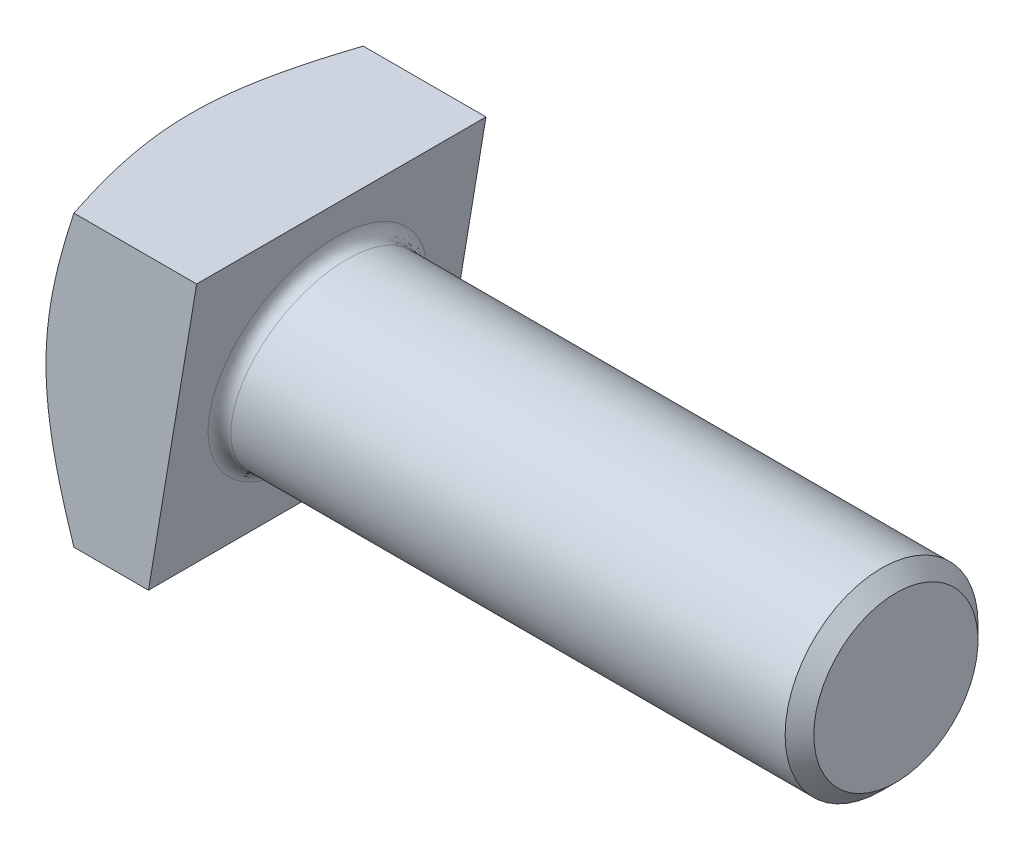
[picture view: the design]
ISO-10303-21;
HEADER;
FILE_DESCRIPTION(('STEP AP214'),'2;1');
FILE_NAME('part.step','',(''),(''),'','','');
FILE_SCHEMA(('AUTOMOTIVE_DESIGN { 1 0 10303 214 1 1 1 1 }'));
ENDSEC;
DATA;
#1=APPLICATION_CONTEXT('core data for automotive mechanical design processes');
#2=APPLICATION_PROTOCOL_DEFINITION('international standard','automotive_design',2000,#1);
#3=PRODUCT_CONTEXT('',#1,'mechanical');
#4=PRODUCT('Part','Part','',(#3));
#5=PRODUCT_RELATED_PRODUCT_CATEGORY('part','',(#4));
#6=PRODUCT_DEFINITION_FORMATION('','',#4);
#7=PRODUCT_DEFINITION_CONTEXT('part definition',#1,'design');
#8=PRODUCT_DEFINITION('design','',#6,#7);
#9=PRODUCT_DEFINITION_SHAPE('','',#8);
#10=(LENGTH_UNIT() NAMED_UNIT(*) SI_UNIT(.MILLI.,.METRE.));
#11=(NAMED_UNIT(*) PLANE_ANGLE_UNIT() SI_UNIT($,.RADIAN.));
#12=(NAMED_UNIT(*) SI_UNIT($,.STERADIAN.) SOLID_ANGLE_UNIT());
#13=UNCERTAINTY_MEASURE_WITH_UNIT(LENGTH_MEASURE(1.E-05),#10,'distance_accuracy_value','');
#14=(GEOMETRIC_REPRESENTATION_CONTEXT(3) GLOBAL_UNCERTAINTY_ASSIGNED_CONTEXT((#13)) GLOBAL_UNIT_ASSIGNED_CONTEXT((#10,
#11,#12)) REPRESENTATION_CONTEXT('',''));
#15=CARTESIAN_POINT('',(0.,0.,0.));
#16=DIRECTION('',(0.,0.,1.));
#17=DIRECTION('',(1.,0.,0.));
#18=AXIS2_PLACEMENT_3D('',#15,#16,#17);
#19=CARTESIAN_POINT('',(13.4958212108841,-19.05,19.05));
#20=DIRECTION('',(0.,-1.,0.));
#21=DIRECTION('',(0.,0.,-1.));
#22=AXIS2_PLACEMENT_3D('',#19,#20,#21);
#23=PLANE('',#22);
#24=DIRECTION('',(-1.,0.,0.));
#25=VECTOR('',#24,1.);
#26=CARTESIAN_POINT('',(13.4958212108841,-19.05,19.05));
#27=LINE('',#26,#25);
#28=CARTESIAN_POINT('',(13.4958212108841,-19.05,19.05));
#29=VERTEX_POINT('',#28);
#30=CARTESIAN_POINT('',(3.67952571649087,-19.05,19.05));
#31=VERTEX_POINT('',#30);
#32=EDGE_CURVE('E122',#29,#31,#27,.T.);
#33=ORIENTED_EDGE('',*,*,#32,.T.);
#34=CARTESIAN_POINT('',(11.2902215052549,-19.05,-38.8419170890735));
#35=CARTESIAN_POINT('',(11.0864153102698,-19.05,-38.3551118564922));
#36=CARTESIAN_POINT('',(10.8832370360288,-19.05,-37.868043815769));
#37=CARTESIAN_POINT('',(10.478273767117,-19.05,-36.893327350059));
#38=CARTESIAN_POINT('',(10.2764887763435,-19.05,-36.4056789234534));
#39=CARTESIAN_POINT('',(9.6734155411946,-19.05,-34.9417460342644));
#40=CARTESIAN_POINT('',(9.27442532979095,-19.05,-33.9645128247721));
#41=CARTESIAN_POINT('',(8.48368559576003,-19.05,-32.0062899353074));
#42=CARTESIAN_POINT('',(8.09194155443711,-19.05,-31.0252980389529));
#43=CARTESIAN_POINT('',(7.31784014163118,-19.05,-29.0596242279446));
#44=CARTESIAN_POINT('',(6.93548265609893,-19.05,-28.0749423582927));
#45=CARTESIAN_POINT('',(6.1781932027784,-19.05,-26.0895493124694));
#46=CARTESIAN_POINT('',(5.8033998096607,-19.05,-25.0887851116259));
#47=CARTESIAN_POINT('',(5.06928185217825,-19.05,-23.081553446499));
#48=CARTESIAN_POINT('',(4.70995768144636,-19.05,-22.075085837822));
#49=CARTESIAN_POINT('',(4.01126573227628,-19.05,-20.0549444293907));
#50=CARTESIAN_POINT('',(3.67190231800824,-19.05,-19.0412691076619));
#51=CARTESIAN_POINT('',(3.18260780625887,-19.05,-17.5144399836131));
#52=CARTESIAN_POINT('',(3.02280262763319,-19.05,-17.004448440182));
#53=CARTESIAN_POINT('',(2.71077373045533,-19.05,-15.9821547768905));
#54=CARTESIAN_POINT('',(2.55854993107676,-19.05,-15.4698526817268));
#55=CARTESIAN_POINT('',(2.18516308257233,-19.05,-14.1731993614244));
#56=CARTESIAN_POINT('',(1.96974702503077,-19.05,-13.3871770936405));
#57=CARTESIAN_POINT('',(1.56373956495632,-19.05,-11.8086936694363));
#58=CARTESIAN_POINT('',(1.37314818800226,-19.05,-11.0162325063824));
#59=CARTESIAN_POINT('',(1.02239164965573,-19.05,-9.42514563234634));
#60=CARTESIAN_POINT('',(0.862204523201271,-19.05,-8.62652480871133));
#61=CARTESIAN_POINT('',(0.578083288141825,-19.05,-7.02274351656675));
#62=CARTESIAN_POINT('',(0.454148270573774,-19.05,-6.21758321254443));
#63=CARTESIAN_POINT('',(0.300005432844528,-19.05,-5.00759649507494));
#64=CARTESIAN_POINT('',(0.253982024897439,-19.05,-4.60475053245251));
#65=CARTESIAN_POINT('',(0.172960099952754,-19.05,-3.79795792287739));
#66=CARTESIAN_POINT('',(0.137961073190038,-19.05,-3.39401132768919));
#67=CARTESIAN_POINT('',(0.0794934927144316,-19.05,-2.58528857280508));
#68=CARTESIAN_POINT('',(0.0560247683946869,-19.05,-2.18051242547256));
#69=CARTESIAN_POINT('',(0.0209711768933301,-19.05,-1.37044257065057));
#70=CARTESIAN_POINT('',(0.00938631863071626,-19.05,-0.965148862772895));
#71=CARTESIAN_POINT('',(-0.00171486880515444,-19.05,-0.154616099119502));
#72=CARTESIAN_POINT('',(-0.00123776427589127,-19.05,0.250622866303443));
#73=CARTESIAN_POINT('',(0.0117608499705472,-19.05,1.06090361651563));
#74=CARTESIAN_POINT('',(0.0242822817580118,-19.05,1.4659454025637));
#75=CARTESIAN_POINT('',(0.0611754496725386,-19.05,2.27549226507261));
#76=CARTESIAN_POINT('',(0.0855473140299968,-19.05,2.6799973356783));
#77=CARTESIAN_POINT('',(0.145770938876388,-19.05,3.48815676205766));
#78=CARTESIAN_POINT('',(0.181623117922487,-19.05,3.89181108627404));
#79=CARTESIAN_POINT('',(0.291723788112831,-19.05,4.96529995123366));
#80=CARTESIAN_POINT('',(0.375668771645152,-19.05,5.63415580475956));
#81=CARTESIAN_POINT('',(0.570959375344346,-19.05,6.96786634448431));
#82=CARTESIAN_POINT('',(0.682308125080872,-19.05,7.63272056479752));
#83=CARTESIAN_POINT('',(0.929086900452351,-19.05,8.95829697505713));
#84=CARTESIAN_POINT('',(1.06453043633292,-19.05,9.61901663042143));
#85=CARTESIAN_POINT('',(1.35607804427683,-19.05,10.9358292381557));
#86=CARTESIAN_POINT('',(1.51218163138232,-19.05,11.5919222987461));
#87=CARTESIAN_POINT('',(1.84291316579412,-19.05,12.9035714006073));
#88=CARTESIAN_POINT('',(2.01764633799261,-19.05,13.5591007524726));
#89=CARTESIAN_POINT('',(2.38205808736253,-19.05,14.8659747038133));
#90=CARTESIAN_POINT('',(2.57173673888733,-19.05,15.517319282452));
#91=CARTESIAN_POINT('',(2.96359176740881,-19.05,16.8160365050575));
#92=CARTESIAN_POINT('',(3.1657648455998,-19.05,17.46341014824));
#93=CARTESIAN_POINT('',(3.58064657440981,-19.05,18.7547595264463));
#94=CARTESIAN_POINT('',(3.793355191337,-19.05,19.3987352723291));
#95=CARTESIAN_POINT('',(4.23720030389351,-19.05,20.7119590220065));
#96=CARTESIAN_POINT('',(4.46873581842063,-19.05,21.3810718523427));
#97=CARTESIAN_POINT('',(4.93991757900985,-19.05,22.7164300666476));
#98=CARTESIAN_POINT('',(5.17956383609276,-19.05,23.3826754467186));
#99=CARTESIAN_POINT('',(5.66571185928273,-19.05,24.712706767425));
#100=CARTESIAN_POINT('',(5.91221408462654,-19.05,25.3764925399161));
#101=CARTESIAN_POINT('',(6.41101892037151,-19.05,26.7018819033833));
#102=CARTESIAN_POINT('',(6.66332156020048,-19.05,27.3634854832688));
#103=CARTESIAN_POINT('',(7.16922259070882,-19.05,28.6753217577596));
#104=CARTESIAN_POINT('',(7.42275067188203,-19.05,29.3255815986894));
#105=CARTESIAN_POINT('',(7.93393740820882,-19.05,30.6244763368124));
#106=CARTESIAN_POINT('',(8.19159607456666,-19.05,31.2731112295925));
#107=CARTESIAN_POINT('',(8.71041202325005,-19.05,32.5687880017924));
#108=CARTESIAN_POINT('',(8.97156840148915,-19.05,33.2158302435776));
#109=CARTESIAN_POINT('',(9.4969882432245,-19.05,34.5086430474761));
#110=CARTESIAN_POINT('',(9.76125166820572,-19.05,35.1544136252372));
#111=CARTESIAN_POINT('',(10.0268440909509,-19.05,35.7996345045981));
#112=B_SPLINE_CURVE_WITH_KNOTS('',3,(#34,#35,#36,#37,#38,#39,#40,#41,#42,#43,#44,#45,#46,#47,
#48,#49,#50,#51,#52,#53,#54,#55,#56,#57,#58,#59,#60,#61,#62,#63,#64,#65,#66,#67,#68,#69,#70,#71,
#72,#73,#74,#75,#76,#77,#78,#79,#80,#81,#82,#83,#84,#85,#86,#87,#88,#89,#90,#91,#92,#93,#94,#95,
#96,#97,#98,#99,#100,#101,#102,#103,#104,#105,#106,#107,#108,#109,#110,#111),.UNSPECIFIED.,.F.,
.F.,(4,2,2,2,2,2,2,2,2,2,2,2,2,2,2,2,2,2,2,2,2,2,2,2,2,2,2,2,2,2,2,2,2,2,2,2,2,2,4),(0.,
1.58323848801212,3.16648140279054,6.33309365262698,9.50201063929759,12.670889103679,
15.8767185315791,19.0826294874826,22.2892387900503,23.8925172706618,25.4957786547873,
27.9404596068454,30.3851430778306,32.8280536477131,35.2709029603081,36.4871758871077,
37.7033925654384,38.9195912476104,40.1357908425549,41.3513283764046,42.5668580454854,
43.7824008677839,44.997988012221,47.0196099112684,49.0414627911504,51.0644529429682,
53.0873956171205,55.1224393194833,57.1574931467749,59.1920119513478,61.2265242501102,
63.3505820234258,65.4746426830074,67.5988459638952,69.7230600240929,71.8168512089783,
73.9106480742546,76.0039137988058,78.0971536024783),.UNSPECIFIED.);
#113=CARTESIAN_POINT('',(0.,-19.05,0.));
#114=VERTEX_POINT('',#113);
#115=EDGE_CURVE('E100',#31,#114,#112,.F.);
#116=ORIENTED_EDGE('',*,*,#115,.T.);
#117=CARTESIAN_POINT('',(3.67952571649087,-19.05,-19.05));
#118=VERTEX_POINT('',#117);
#119=EDGE_CURVE('E112',#114,#118,#112,.F.);
#120=ORIENTED_EDGE('',*,*,#119,.T.);
#121=DIRECTION('',(-1.,0.,0.));
#122=VECTOR('',#121,1.);
#123=CARTESIAN_POINT('',(13.4958212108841,-19.05,-19.05));
#124=LINE('',#123,#122);
#125=CARTESIAN_POINT('',(13.4958212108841,-19.05,-19.05));
#126=VERTEX_POINT('',#125);
#127=EDGE_CURVE('E287',#126,#118,#124,.T.);
#128=ORIENTED_EDGE('',*,*,#127,.F.);
#129=DIRECTION('',(0.,0.,-1.));
#130=VECTOR('',#129,1.);
#131=CARTESIAN_POINT('',(13.4958212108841,-19.05,19.05));
#132=LINE('',#131,#130);
#133=EDGE_CURVE('E307',#29,#126,#132,.T.);
#134=ORIENTED_EDGE('',*,*,#133,.F.);
#135=EDGE_LOOP('',(#33,#116,#120,#128,#134));
#136=FACE_BOUND('',#135,.T.);
#137=ADVANCED_FACE('F39',(#136),#23,.T.);
#138=CARTESIAN_POINT('',(0.,19.05,19.05));
#139=DIRECTION('',(0.,1.,0.));
#140=DIRECTION('',(-1.,0.,0.));
#141=AXIS2_PLACEMENT_3D('',#138,#139,#140);
#142=PLANE('',#141);
#143=DIRECTION('',(1.,0.,0.));
#144=VECTOR('',#143,1.);
#145=CARTESIAN_POINT('',(0.,19.05,-19.05));
#146=LINE('',#145,#144);
#147=CARTESIAN_POINT('',(3.67952571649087,19.05,-19.05));
#148=VERTEX_POINT('',#147);
#149=CARTESIAN_POINT('',(19.8374,19.05,-19.05));
#150=VERTEX_POINT('',#149);
#151=EDGE_CURVE('E303',#148,#150,#146,.T.);
#152=ORIENTED_EDGE('',*,*,#151,.F.);
#153=CARTESIAN_POINT('',(11.290221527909,19.05,-38.8419171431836));
#154=CARTESIAN_POINT('',(11.08641533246,19.05,-38.3551119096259));
#155=CARTESIAN_POINT('',(10.8832370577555,19.05,-37.868043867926));
#156=CARTESIAN_POINT('',(10.4782737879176,19.05,-36.8933274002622));
#157=CARTESIAN_POINT('',(10.2764887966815,19.05,-36.4056789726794));
#158=CARTESIAN_POINT('',(9.67341556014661,19.05,-34.9417460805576));
#159=CARTESIAN_POINT('',(9.27442534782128,19.05,-33.9645128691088));
#160=CARTESIAN_POINT('',(8.48368561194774,19.05,-32.0062899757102));
#161=CARTESIAN_POINT('',(8.09194156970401,19.05,-31.0252980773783));
#162=CARTESIAN_POINT('',(7.31784015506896,19.05,-29.0596242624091));
#163=CARTESIAN_POINT('',(6.93548266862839,19.05,-28.0749423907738));
#164=CARTESIAN_POINT('',(6.17819321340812,19.05,-26.0895493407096));
#165=CARTESIAN_POINT('',(5.80339981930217,19.05,-25.0887851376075));
#166=CARTESIAN_POINT('',(5.06928185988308,19.05,-23.081553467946));
#167=CARTESIAN_POINT('',(4.70995768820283,19.05,-22.0750858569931));
#168=CARTESIAN_POINT('',(4.01126573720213,19.05,-20.0549444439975));
#169=CARTESIAN_POINT('',(3.67190232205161,19.05,-19.0412691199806));
#170=CARTESIAN_POINT('',(3.18260780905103,19.05,-17.5144399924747));
#171=CARTESIAN_POINT('',(3.02280263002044,19.05,-17.0044484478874));
#172=CARTESIAN_POINT('',(2.71077373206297,19.05,-15.9821547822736));
#173=CARTESIAN_POINT('',(2.55854993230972,19.05,-15.4698526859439));
#174=CARTESIAN_POINT('',(2.18516308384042,19.05,-14.1731993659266));
#175=CARTESIAN_POINT('',(1.96974702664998,19.05,-13.3871770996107));
#176=CARTESIAN_POINT('',(1.56373956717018,19.05,-11.8086936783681));
#177=CARTESIAN_POINT('',(1.37314819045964,19.05,-11.0162325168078));
#178=CARTESIAN_POINT('',(1.02239165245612,19.05,-9.42514564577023));
#179=CARTESIAN_POINT('',(0.862204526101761,19.05,-8.62652482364));
#180=CARTESIAN_POINT('',(0.578083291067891,19.05,-7.02274353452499));
#181=CARTESIAN_POINT('',(0.454148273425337,19.05,-6.21758323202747));
#182=CARTESIAN_POINT('',(0.300005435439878,19.05,-5.00759651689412));
#183=CARTESIAN_POINT('',(0.253982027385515,19.05,-4.60475055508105));
#184=CARTESIAN_POINT('',(0.172960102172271,19.05,-3.79795794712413));
#185=CARTESIAN_POINT('',(0.137961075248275,19.05,-3.39401135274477));
#186=CARTESIAN_POINT('',(0.0794934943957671,19.05,-2.58528859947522));
#187=CARTESIAN_POINT('',(0.056024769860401,19.05,-2.1805124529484));
#188=CARTESIAN_POINT('',(0.0209711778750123,19.05,-1.37044259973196));
#189=CARTESIAN_POINT('',(0.009386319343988,19.05,-0.965148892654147));
#190=CARTESIAN_POINT('',(-0.00171486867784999,19.05,-0.15461613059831));
#191=CARTESIAN_POINT('',(-0.00123776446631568,19.05,0.250622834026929));
#192=CARTESIAN_POINT('',(0.0117608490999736,19.05,1.0609035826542));
#193=CARTESIAN_POINT('',(0.024282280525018,19.05,1.46594536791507));
#194=CARTESIAN_POINT('',(0.0611754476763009,19.05,2.27549222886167));
#195=CARTESIAN_POINT('',(0.08554731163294,19.05,2.67999729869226));
#196=CARTESIAN_POINT('',(0.145770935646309,19.05,3.48815672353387));
#197=CARTESIAN_POINT('',(0.1816231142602,19.05,3.89181104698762));
#198=CARTESIAN_POINT('',(0.291723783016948,19.05,4.96529990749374));
#199=CARTESIAN_POINT('',(0.375668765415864,19.05,5.63415575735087));
#200=CARTESIAN_POINT('',(0.570959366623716,19.05,6.96786628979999));
#201=CARTESIAN_POINT('',(0.682308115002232,19.05,7.63272050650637));
#202=CARTESIAN_POINT('',(0.929086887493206,19.05,8.95829690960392));
#203=CARTESIAN_POINT('',(1.064530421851,19.05,9.61901656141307));
#204=CARTESIAN_POINT('',(1.35607802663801,19.05,10.9358291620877));
#205=CARTESIAN_POINT('',(1.5121816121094,19.05,11.5919222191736));
#206=CARTESIAN_POINT('',(1.84291314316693,19.05,12.9035713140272));
#207=CARTESIAN_POINT('',(2.01764631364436,19.05,13.5591006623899));
#208=CARTESIAN_POINT('',(2.38205805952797,19.05,14.8659746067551));
#209=CARTESIAN_POINT('',(2.5717367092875,19.05,15.5173191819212));
#210=CARTESIAN_POINT('',(2.96359173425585,19.05,16.8160363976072));
#211=CARTESIAN_POINT('',(3.16576481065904,19.05,17.4634100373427));
#212=CARTESIAN_POINT('',(3.58064653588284,19.05,18.7547594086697));
#213=CARTESIAN_POINT('',(3.79335515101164,19.05,19.3987351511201));
#214=CARTESIAN_POINT('',(4.23720025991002,19.05,20.7119588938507));
#215=CARTESIAN_POINT('',(4.46873577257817,19.05,21.3810717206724));
#216=CARTESIAN_POINT('',(4.93991752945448,19.05,22.716429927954));
#217=CARTESIAN_POINT('',(5.17956378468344,19.05,23.3826753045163));
#218=CARTESIAN_POINT('',(5.66571180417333,19.05,24.7127066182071));
#219=CARTESIAN_POINT('',(5.91221402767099,19.05,25.3764923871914));
#220=CARTESIAN_POINT('',(6.41101885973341,19.05,26.701881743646));
#221=CARTESIAN_POINT('',(6.66332149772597,19.05,27.3634853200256));
#222=CARTESIAN_POINT('',(7.16922252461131,19.05,28.6753215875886));
#223=CARTESIAN_POINT('',(7.42275060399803,19.05,29.3255814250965));
#224=CARTESIAN_POINT('',(7.93393733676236,19.05,30.6244761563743));
#225=CARTESIAN_POINT('',(8.19159600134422,19.05,31.2731110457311));
#226=CARTESIAN_POINT('',(8.71041194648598,19.05,32.5687878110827));
#227=CARTESIAN_POINT('',(8.97156832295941,19.05,33.2158300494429));
#228=CARTESIAN_POINT('',(9.496988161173,19.05,34.5086428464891));
#229=CARTESIAN_POINT('',(9.76125158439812,19.05,35.154413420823));
#230=CARTESIAN_POINT('',(10.0268440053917,19.05,35.7996342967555));
#231=B_SPLINE_CURVE_WITH_KNOTS('',3,(#153,#154,#155,#156,#157,#158,#159,#160,#161,#162,#163,
#164,#165,#166,#167,#168,#169,#170,#171,#172,#173,#174,#175,#176,#177,#178,#179,#180,#181,#182,
#183,#184,#185,#186,#187,#188,#189,#190,#191,#192,#193,#194,#195,#196,#197,#198,#199,#200,#201,
#202,#203,#204,#205,#206,#207,#208,#209,#210,#211,#212,#213,#214,#215,#216,#217,#218,#219,#220,
#221,#222,#223,#224,#225,#226,#227,#228,#229,#230),.UNSPECIFIED.,.F.,.F.,(4,2,2,2,2,2,2,2,2,2,2,
2,2,2,2,2,2,2,2,2,2,2,2,2,2,2,2,2,2,2,2,2,2,2,2,2,2,2,4),(0.,1.58323849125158,3.16648140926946,
6.33309366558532,9.50201065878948,12.6708891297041,15.8767185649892,19.0826295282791,
22.2892388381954,23.89251732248,25.4957787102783,27.9404596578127,30.385143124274,
32.8280536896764,35.2709029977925,36.4871759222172,37.7033925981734,38.919591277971,
40.1357908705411,41.3513284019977,42.5668580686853,43.7824008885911,44.9979880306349,
47.0196099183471,49.0414627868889,51.0644529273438,53.0873955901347,55.1224392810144,
57.1574930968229,59.1920118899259,61.2265241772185,63.3505819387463,65.4746425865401,
67.5988458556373,69.7230599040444,71.8168510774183,73.9106479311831,76.0039136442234,
78.0971534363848),.UNSPECIFIED.);
#232=CARTESIAN_POINT('',(0.,19.05,0.));
#233=VERTEX_POINT('',#232);
#234=EDGE_CURVE('E106',#148,#233,#231,.T.);
#235=ORIENTED_EDGE('',*,*,#234,.T.);
#236=CARTESIAN_POINT('',(3.67952571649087,19.05,19.05));
#237=VERTEX_POINT('',#236);
#238=EDGE_CURVE('E132',#233,#237,#231,.T.);
#239=ORIENTED_EDGE('',*,*,#238,.T.);
#240=DIRECTION('',(1.,0.,0.));
#241=VECTOR('',#240,1.);
#242=CARTESIAN_POINT('',(0.,19.05,19.05));
#243=LINE('',#242,#241);
#244=CARTESIAN_POINT('',(19.8374,19.05,19.05));
#245=VERTEX_POINT('',#244);
#246=EDGE_CURVE('E291',#237,#245,#243,.T.);
#247=ORIENTED_EDGE('',*,*,#246,.T.);
#248=DIRECTION('',(0.,0.,-1.));
#249=VECTOR('',#248,1.);
#250=CARTESIAN_POINT('',(19.8374,19.05,19.05));
#251=LINE('',#250,#249);
#252=EDGE_CURVE('E297',#245,#150,#251,.T.);
#253=ORIENTED_EDGE('',*,*,#252,.T.);
#254=EDGE_LOOP('',(#152,#235,#239,#247,#253));
#255=FACE_BOUND('',#254,.T.);
#256=ADVANCED_FACE('F138',(#255),#142,.T.);
#257=CARTESIAN_POINT('',(0.,-19.05,19.05));
#258=DIRECTION('',(0.,0.,-1.));
#259=DIRECTION('',(-1.,0.,0.));
#260=AXIS2_PLACEMENT_3D('',#257,#258,#259);
#261=PLANE('',#260);
#262=CARTESIAN_POINT('',(11.2902215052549,-38.8419170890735,19.05));
#263=CARTESIAN_POINT('',(11.0864153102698,-38.3551118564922,19.05));
#264=CARTESIAN_POINT('',(10.8832370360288,-37.868043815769,19.05));
#265=CARTESIAN_POINT('',(10.478273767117,-36.893327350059,19.05));
#266=CARTESIAN_POINT('',(10.2764887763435,-36.4056789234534,19.05));
#267=CARTESIAN_POINT('',(9.67341554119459,-34.9417460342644,19.05));
#268=CARTESIAN_POINT('',(9.27442532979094,-33.9645128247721,19.05));
#269=CARTESIAN_POINT('',(8.48368559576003,-32.0062899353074,19.05));
#270=CARTESIAN_POINT('',(8.09194155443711,-31.0252980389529,19.05));
#271=CARTESIAN_POINT('',(7.31784014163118,-29.0596242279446,19.05));
#272=CARTESIAN_POINT('',(6.93548265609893,-28.0749423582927,19.05));
#273=CARTESIAN_POINT('',(6.1781932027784,-26.0895493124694,19.05));
#274=CARTESIAN_POINT('',(5.8033998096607,-25.0887851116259,19.05));
#275=CARTESIAN_POINT('',(5.06928185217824,-23.081553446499,19.05));
#276=CARTESIAN_POINT('',(4.70995768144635,-22.075085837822,19.05));
#277=CARTESIAN_POINT('',(4.01126573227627,-20.0549444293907,19.05));
#278=CARTESIAN_POINT('',(3.67190231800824,-19.0412691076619,19.05));
#279=CARTESIAN_POINT('',(3.18260780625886,-17.5144399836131,19.05));
#280=CARTESIAN_POINT('',(3.02280262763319,-17.004448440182,19.05));
#281=CARTESIAN_POINT('',(2.71077373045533,-15.9821547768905,19.05));
#282=CARTESIAN_POINT('',(2.55854993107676,-15.4698526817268,19.05));
#283=CARTESIAN_POINT('',(2.18516308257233,-14.1731993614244,19.05));
#284=CARTESIAN_POINT('',(1.96974702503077,-13.3871770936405,19.05));
#285=CARTESIAN_POINT('',(1.56373956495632,-11.8086936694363,19.05));
#286=CARTESIAN_POINT('',(1.37314818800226,-11.0162325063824,19.05));
#287=CARTESIAN_POINT('',(1.02239164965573,-9.42514563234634,19.05));
#288=CARTESIAN_POINT('',(0.862204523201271,-8.62652480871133,19.05));
#289=CARTESIAN_POINT('',(0.578083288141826,-7.02274351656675,19.05));
#290=CARTESIAN_POINT('',(0.454148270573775,-6.21758321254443,19.05));
#291=CARTESIAN_POINT('',(0.300005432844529,-5.00759649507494,19.05));
#292=CARTESIAN_POINT('',(0.25398202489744,-4.60475053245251,19.05));
#293=CARTESIAN_POINT('',(0.172960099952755,-3.79795792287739,19.05));
#294=CARTESIAN_POINT('',(0.137961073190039,-3.39401132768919,19.05));
#295=CARTESIAN_POINT('',(0.0794934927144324,-2.58528857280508,19.05));
#296=CARTESIAN_POINT('',(0.0560247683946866,-2.18051242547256,19.05));
#297=CARTESIAN_POINT('',(0.0209711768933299,-1.37044257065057,19.05));
#298=CARTESIAN_POINT('',(0.00938631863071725,-0.965148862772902,19.05));
#299=CARTESIAN_POINT('',(-0.00171486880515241,-0.15461609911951,19.05));
#300=CARTESIAN_POINT('',(-0.0012377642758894,0.250622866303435,19.05));
#301=CARTESIAN_POINT('',(0.0117608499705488,1.06090361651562,19.05));
#302=CARTESIAN_POINT('',(0.0242822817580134,1.46594540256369,19.05));
#303=CARTESIAN_POINT('',(0.0611754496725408,2.2754922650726,19.05));
#304=CARTESIAN_POINT('',(0.0855473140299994,2.6799973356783,19.05));
#305=CARTESIAN_POINT('',(0.14577093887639,3.48815676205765,19.05));
#306=CARTESIAN_POINT('',(0.181623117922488,3.89181108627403,19.05));
#307=CARTESIAN_POINT('',(0.291723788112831,4.96529995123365,19.05));
#308=CARTESIAN_POINT('',(0.375668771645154,5.63415580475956,19.05));
#309=CARTESIAN_POINT('',(0.570959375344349,6.9678663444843,19.05));
#310=CARTESIAN_POINT('',(0.682308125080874,7.63272056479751,19.05));
#311=CARTESIAN_POINT('',(0.929086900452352,8.95829697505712,19.05));
#312=CARTESIAN_POINT('',(1.06453043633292,9.61901663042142,19.05));
#313=CARTESIAN_POINT('',(1.35607804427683,10.9358292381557,19.05));
#314=CARTESIAN_POINT('',(1.51218163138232,11.5919222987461,19.05));
#315=CARTESIAN_POINT('',(1.84291316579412,12.9035714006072,19.05));
#316=CARTESIAN_POINT('',(2.01764633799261,13.5591007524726,19.05));
#317=CARTESIAN_POINT('',(2.38205808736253,14.8659747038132,19.05));
#318=CARTESIAN_POINT('',(2.57173673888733,15.5173192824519,19.05));
#319=CARTESIAN_POINT('',(2.96359176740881,16.8160365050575,19.05));
#320=CARTESIAN_POINT('',(3.1657648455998,17.46341014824,19.05));
#321=CARTESIAN_POINT('',(3.58064657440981,18.7547595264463,19.05));
#322=CARTESIAN_POINT('',(3.793355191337,19.398735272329,19.05));
#323=CARTESIAN_POINT('',(4.23720030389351,20.7119590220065,19.05));
#324=CARTESIAN_POINT('',(4.46873581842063,21.3810718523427,19.05));
#325=CARTESIAN_POINT('',(4.93991757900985,22.7164300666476,19.05));
#326=CARTESIAN_POINT('',(5.17956383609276,23.3826754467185,19.05));
#327=CARTESIAN_POINT('',(5.66571185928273,24.712706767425,19.05));
#328=CARTESIAN_POINT('',(5.91221408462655,25.3764925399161,19.05));
#329=CARTESIAN_POINT('',(6.41101892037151,26.7018819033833,19.05));
#330=CARTESIAN_POINT('',(6.66332156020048,27.3634854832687,19.05));
#331=CARTESIAN_POINT('',(7.16922259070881,28.6753217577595,19.05));
#332=CARTESIAN_POINT('',(7.42275067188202,29.3255815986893,19.05));
#333=CARTESIAN_POINT('',(7.93393740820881,30.6244763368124,19.05));
#334=CARTESIAN_POINT('',(8.19159607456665,31.2731112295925,19.05));
#335=CARTESIAN_POINT('',(8.71041202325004,32.5687880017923,19.05));
#336=CARTESIAN_POINT('',(8.97156840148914,33.2158302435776,19.05));
#337=CARTESIAN_POINT('',(9.49698824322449,34.508643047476,19.05));
#338=CARTESIAN_POINT('',(9.76125166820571,35.1544136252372,19.05));
#339=CARTESIAN_POINT('',(10.0268440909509,35.7996345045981,19.05));
#340=B_SPLINE_CURVE_WITH_KNOTS('',3,(#262,#263,#264,#265,#266,#267,#268,#269,#270,#271,#272,
#273,#274,#275,#276,#277,#278,#279,#280,#281,#282,#283,#284,#285,#286,#287,#288,#289,#290,#291,
#292,#293,#294,#295,#296,#297,#298,#299,#300,#301,#302,#303,#304,#305,#306,#307,#308,#309,#310,
#311,#312,#313,#314,#315,#316,#317,#318,#319,#320,#321,#322,#323,#324,#325,#326,#327,#328,#329,
#330,#331,#332,#333,#334,#335,#336,#337,#338,#339),.UNSPECIFIED.,.F.,.F.,(4,2,2,2,2,2,2,2,2,2,2,
2,2,2,2,2,2,2,2,2,2,2,2,2,2,2,2,2,2,2,2,2,2,2,2,2,2,2,4),(0.,1.58323848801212,3.16648140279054,
6.33309365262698,9.50201063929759,12.670889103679,15.8767185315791,19.0826294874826,
22.2892387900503,23.8925172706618,25.4957786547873,27.9404596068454,30.3851430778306,
32.8280536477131,35.2709029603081,36.4871758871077,37.7033925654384,38.9195912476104,
40.1357908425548,41.3513283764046,42.5668580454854,43.7824008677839,44.997988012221,
47.0196099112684,49.0414627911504,51.0644529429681,53.0873956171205,55.1224393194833,
57.1574931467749,59.1920119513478,61.2265242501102,63.3505820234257,65.4746426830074,
67.5988459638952,69.7230600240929,71.8168512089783,73.9106480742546,76.0039137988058,
78.0971536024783),.UNSPECIFIED.);
#341=CARTESIAN_POINT('',(0.,0.,19.05));
#342=VERTEX_POINT('',#341);
#343=EDGE_CURVE('E101',#31,#342,#340,.T.);
#344=ORIENTED_EDGE('',*,*,#343,.F.);
#345=ORIENTED_EDGE('',*,*,#32,.F.);
#346=DIRECTION('',(-0.164186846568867,-0.986429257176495,0.));
#347=VECTOR('',#346,1.);
#348=CARTESIAN_POINT('',(19.8374,19.05,19.05));
#349=LINE('',#348,#347);
#350=EDGE_CURVE('E295',#245,#29,#349,.T.);
#351=ORIENTED_EDGE('',*,*,#350,.F.);
#352=ORIENTED_EDGE('',*,*,#246,.F.);
#353=EDGE_CURVE('E65',#342,#237,#340,.T.);
#354=ORIENTED_EDGE('',*,*,#353,.F.);
#355=EDGE_LOOP('',(#344,#345,#351,#352,#354));
#356=FACE_BOUND('',#355,.T.);
#357=ADVANCED_FACE('F168',(#356),#261,.F.);
#358=CARTESIAN_POINT('',(0.,-19.05,-19.05));
#359=DIRECTION('',(0.,0.,-1.));
#360=DIRECTION('',(-1.,0.,0.));
#361=AXIS2_PLACEMENT_3D('',#358,#359,#360);
#362=PLANE('',#361);
#363=ORIENTED_EDGE('',*,*,#127,.T.);
#364=CARTESIAN_POINT('',(11.2902215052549,-38.8419170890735,-19.05));
#365=CARTESIAN_POINT('',(11.0864153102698,-38.3551118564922,-19.05));
#366=CARTESIAN_POINT('',(10.8832370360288,-37.868043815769,-19.05));
#367=CARTESIAN_POINT('',(10.478273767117,-36.893327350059,-19.05));
#368=CARTESIAN_POINT('',(10.2764887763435,-36.4056789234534,-19.05));
#369=CARTESIAN_POINT('',(9.67341554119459,-34.9417460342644,-19.05));
#370=CARTESIAN_POINT('',(9.27442532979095,-33.9645128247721,-19.05));
#371=CARTESIAN_POINT('',(8.48368559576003,-32.0062899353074,-19.05));
#372=CARTESIAN_POINT('',(8.09194155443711,-31.0252980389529,-19.05));
#373=CARTESIAN_POINT('',(7.31784014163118,-29.0596242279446,-19.05));
#374=CARTESIAN_POINT('',(6.93548265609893,-28.0749423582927,-19.05));
#375=CARTESIAN_POINT('',(6.17819320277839,-26.0895493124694,-19.05));
#376=CARTESIAN_POINT('',(5.80339980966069,-25.0887851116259,-19.05));
#377=CARTESIAN_POINT('',(5.06928185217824,-23.0815534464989,-19.05));
#378=CARTESIAN_POINT('',(4.70995768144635,-22.075085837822,-19.05));
#379=CARTESIAN_POINT('',(4.01126573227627,-20.0549444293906,-19.05));
#380=CARTESIAN_POINT('',(3.67190231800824,-19.0412691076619,-19.05));
#381=CARTESIAN_POINT('',(3.18260780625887,-17.5144399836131,-19.05));
#382=CARTESIAN_POINT('',(3.02280262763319,-17.004448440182,-19.05));
#383=CARTESIAN_POINT('',(2.71077373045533,-15.9821547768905,-19.05));
#384=CARTESIAN_POINT('',(2.55854993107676,-15.4698526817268,-19.05));
#385=CARTESIAN_POINT('',(2.18516308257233,-14.1731993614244,-19.05));
#386=CARTESIAN_POINT('',(1.96974702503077,-13.3871770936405,-19.05));
#387=CARTESIAN_POINT('',(1.56373956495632,-11.8086936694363,-19.05));
#388=CARTESIAN_POINT('',(1.37314818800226,-11.0162325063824,-19.05));
#389=CARTESIAN_POINT('',(1.02239164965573,-9.42514563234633,-19.05));
#390=CARTESIAN_POINT('',(0.862204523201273,-8.62652480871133,-19.05));
#391=CARTESIAN_POINT('',(0.578083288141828,-7.02274351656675,-19.05));
#392=CARTESIAN_POINT('',(0.454148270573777,-6.21758321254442,-19.05));
#393=CARTESIAN_POINT('',(0.300005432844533,-5.00759649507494,-19.05));
#394=CARTESIAN_POINT('',(0.253982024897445,-4.60475053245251,-19.05));
#395=CARTESIAN_POINT('',(0.17296009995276,-3.79795792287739,-19.05));
#396=CARTESIAN_POINT('',(0.137961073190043,-3.39401132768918,-19.05));
#397=CARTESIAN_POINT('',(0.0794934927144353,-2.58528857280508,-19.05));
#398=CARTESIAN_POINT('',(0.0560247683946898,-2.18051242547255,-19.05));
#399=CARTESIAN_POINT('',(0.0209711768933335,-1.37044257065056,-19.05));
#400=CARTESIAN_POINT('',(0.0093863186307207,-0.965148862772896,-19.05));
#401=CARTESIAN_POINT('',(-0.00171486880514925,-0.154616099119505,-19.05));
#402=CARTESIAN_POINT('',(-0.00123776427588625,0.250622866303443,-19.05));
#403=CARTESIAN_POINT('',(0.0117608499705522,1.06090361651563,-19.05));
#404=CARTESIAN_POINT('',(0.024282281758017,1.4659454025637,-19.05));
#405=CARTESIAN_POINT('',(0.061175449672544,2.27549226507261,-19.05));
#406=CARTESIAN_POINT('',(0.0855473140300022,2.6799973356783,-19.05));
#407=CARTESIAN_POINT('',(0.145770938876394,3.48815676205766,-19.05));
#408=CARTESIAN_POINT('',(0.181623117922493,3.89181108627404,-19.05));
#409=CARTESIAN_POINT('',(0.291723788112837,4.96529995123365,-19.05));
#410=CARTESIAN_POINT('',(0.375668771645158,5.63415580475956,-19.05));
#411=CARTESIAN_POINT('',(0.570959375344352,6.96786634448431,-19.05));
#412=CARTESIAN_POINT('',(0.68230812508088,7.63272056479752,-19.05));
#413=CARTESIAN_POINT('',(0.929086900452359,8.95829697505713,-19.05));
#414=CARTESIAN_POINT('',(1.06453043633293,9.61901663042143,-19.05));
#415=CARTESIAN_POINT('',(1.35607804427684,10.9358292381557,-19.05));
#416=CARTESIAN_POINT('',(1.51218163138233,11.5919222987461,-19.05));
#417=CARTESIAN_POINT('',(1.84291316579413,12.9035714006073,-19.05));
#418=CARTESIAN_POINT('',(2.01764633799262,13.5591007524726,-19.05));
#419=CARTESIAN_POINT('',(2.38205808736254,14.8659747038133,-19.05));
#420=CARTESIAN_POINT('',(2.57173673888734,15.517319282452,-19.05));
#421=CARTESIAN_POINT('',(2.96359176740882,16.8160365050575,-19.05));
#422=CARTESIAN_POINT('',(3.16576484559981,17.46341014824,-19.05));
#423=CARTESIAN_POINT('',(3.58064657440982,18.7547595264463,-19.05));
#424=CARTESIAN_POINT('',(3.79335519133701,19.3987352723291,-19.05));
#425=CARTESIAN_POINT('',(4.23720030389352,20.7119590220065,-19.05));
#426=CARTESIAN_POINT('',(4.46873581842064,21.3810718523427,-19.05));
#427=CARTESIAN_POINT('',(4.93991757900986,22.7164300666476,-19.05));
#428=CARTESIAN_POINT('',(5.17956383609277,23.3826754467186,-19.05));
#429=CARTESIAN_POINT('',(5.66571185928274,24.712706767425,-19.05));
#430=CARTESIAN_POINT('',(5.91221408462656,25.3764925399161,-19.05));
#431=CARTESIAN_POINT('',(6.41101892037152,26.7018819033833,-19.05));
#432=CARTESIAN_POINT('',(6.66332156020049,27.3634854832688,-19.05));
#433=CARTESIAN_POINT('',(7.16922259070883,28.6753217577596,-19.05));
#434=CARTESIAN_POINT('',(7.42275067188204,29.3255815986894,-19.05));
#435=CARTESIAN_POINT('',(7.93393740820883,30.6244763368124,-19.05));
#436=CARTESIAN_POINT('',(8.19159607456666,31.2731112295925,-19.05));
#437=CARTESIAN_POINT('',(8.71041202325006,32.5687880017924,-19.05));
#438=CARTESIAN_POINT('',(8.97156840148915,33.2158302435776,-19.05));
#439=CARTESIAN_POINT('',(9.49698824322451,34.508643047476,-19.05));
#440=CARTESIAN_POINT('',(9.76125166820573,35.1544136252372,-19.05));
#441=CARTESIAN_POINT('',(10.0268440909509,35.7996345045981,-19.05));
#442=B_SPLINE_CURVE_WITH_KNOTS('',3,(#364,#365,#366,#367,#368,#369,#370,#371,#372,#373,#374,
#375,#376,#377,#378,#379,#380,#381,#382,#383,#384,#385,#386,#387,#388,#389,#390,#391,#392,#393,
#394,#395,#396,#397,#398,#399,#400,#401,#402,#403,#404,#405,#406,#407,#408,#409,#410,#411,#412,
#413,#414,#415,#416,#417,#418,#419,#420,#421,#422,#423,#424,#425,#426,#427,#428,#429,#430,#431,
#432,#433,#434,#435,#436,#437,#438,#439,#440,#441),.UNSPECIFIED.,.F.,.F.,(4,2,2,2,2,2,2,2,2,2,2,
2,2,2,2,2,2,2,2,2,2,2,2,2,2,2,2,2,2,2,2,2,2,2,2,2,2,2,4),(0.,1.58323848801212,3.16648140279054,
6.33309365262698,9.50201063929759,12.670889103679,15.8767185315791,19.0826294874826,
22.2892387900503,23.8925172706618,25.4957786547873,27.9404596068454,30.3851430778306,
32.8280536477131,35.2709029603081,36.4871758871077,37.7033925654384,38.9195912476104,
40.1357908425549,41.3513283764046,42.5668580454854,43.7824008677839,44.997988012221,
47.0196099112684,49.0414627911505,51.0644529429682,53.0873956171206,55.1224393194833,
57.1574931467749,59.1920119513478,61.2265242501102,63.3505820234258,65.4746426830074,
67.5988459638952,69.723060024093,71.8168512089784,73.9106480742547,76.0039137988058,
78.0971536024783),.UNSPECIFIED.);
#443=CARTESIAN_POINT('',(0.,0.,-19.05));
#444=VERTEX_POINT('',#443);
#445=EDGE_CURVE('E115',#118,#444,#442,.T.);
#446=ORIENTED_EDGE('',*,*,#445,.T.);
#447=EDGE_CURVE('E151',#444,#148,#442,.T.);
#448=ORIENTED_EDGE('',*,*,#447,.T.);
#449=ORIENTED_EDGE('',*,*,#151,.T.);
#450=DIRECTION('',(-0.164186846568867,-0.986429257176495,0.));
#451=VECTOR('',#450,1.);
#452=CARTESIAN_POINT('',(19.8374,19.05,-19.05));
#453=LINE('',#452,#451);
#454=EDGE_CURVE('E299',#150,#126,#453,.T.);
#455=ORIENTED_EDGE('',*,*,#454,.T.);
#456=EDGE_LOOP('',(#363,#446,#448,#449,#455));
#457=FACE_BOUND('',#456,.T.);
#458=ADVANCED_FACE('F171',(#457),#362,.T.);
#459=CARTESIAN_POINT('',(19.8374,19.05,19.05));
#460=DIRECTION('',(0.986429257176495,-0.164186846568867,0.));
#461=DIRECTION('',(0.164186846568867,0.986429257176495,0.));
#462=AXIS2_PLACEMENT_3D('',#459,#460,#461);
#463=PLANE('',#462);
#464=CARTESIAN_POINT('',(16.7082587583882,0.250220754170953,0.));
#465=DIRECTION('',(0.986429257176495,-0.164186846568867,0.));
#466=DIRECTION('',(-0.164186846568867,-0.986429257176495,0.));
#467=AXIS2_PLACEMENT_3D('',#464,#465,#466);
#468=ELLIPSE('',#467,14.4196858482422,14.224);
#469=CARTESIAN_POINT('',(14.3407360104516,-13.973779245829,0.));
#470=VERTEX_POINT('',#469);
#471=EDGE_CURVE('E11',#470,#470,#468,.F.);
#472=ORIENTED_EDGE('',*,*,#471,.T.);
#473=EDGE_LOOP('',(#472));
#474=FACE_BOUND('',#473,.T.);
#475=ORIENTED_EDGE('',*,*,#454,.F.);
#476=ORIENTED_EDGE('',*,*,#252,.F.);
#477=ORIENTED_EDGE('',*,*,#350,.T.);
#478=ORIENTED_EDGE('',*,*,#133,.T.);
#479=EDGE_LOOP('',(#475,#476,#477,#478));
#480=FACE_BOUND('',#479,.T.);
#481=ADVANCED_FACE('F176',(#474,#480),#463,.T.);
#482=CARTESIAN_POINT('',(0.,0.,0.));
#483=DIRECTION('',(-1.,0.,0.));
#484=DIRECTION('',(0.,0.,1.));
#485=AXIS2_PLACEMENT_3D('',#482,#483,#484);
#486=CYLINDRICAL_SURFACE('',#485,12.7);
#487=CARTESIAN_POINT('',(18.2115769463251,0.,0.));
#488=DIRECTION('',(-0.983064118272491,0.183261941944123,0.));
#489=DIRECTION('',(-0.183261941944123,-0.98306411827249,0.));
#490=AXIS2_PLACEMENT_3D('',#487,#488,#489);
#491=ELLIPSE('',#490,12.9187911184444,12.7);
#492=CARTESIAN_POINT('',(15.8440541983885,-12.7,0.));
#493=VERTEX_POINT('',#492);
#494=EDGE_CURVE('E50',#493,#493,#491,.F.);
#495=ORIENTED_EDGE('',*,*,#494,.T.);
#496=EDGE_LOOP('',(#495));
#497=FACE_BOUND('',#496,.T.);
#498=CARTESIAN_POINT('',(90.9768506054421,0.,0.));
#499=DIRECTION('',(-1.,0.,0.));
#500=DIRECTION('',(0.,0.,1.));
#501=AXIS2_PLACEMENT_3D('',#498,#499,#500);
#502=CIRCLE('',#501,12.7);
#503=CARTESIAN_POINT('',(90.9768506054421,0.,12.7));
#504=VERTEX_POINT('',#503);
#505=EDGE_CURVE('E285',#504,#504,#502,.T.);
#506=ORIENTED_EDGE('',*,*,#505,.T.);
#507=EDGE_LOOP('',(#506));
#508=FACE_BOUND('',#507,.T.);
#509=ADVANCED_FACE('F172',(#497,#508),#486,.T.);
#510=CARTESIAN_POINT('',(90.9768506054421,0.,0.));
#511=DIRECTION('',(-1.,0.,0.));
#512=DIRECTION('',(0.,0.,1.));
#513=AXIS2_PLACEMENT_3D('',#510,#511,#512);
#514=CONICAL_SURFACE('',#513,12.7,0.785398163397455);
#515=CARTESIAN_POINT('',(92.8666106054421,0.,0.));
#516=DIRECTION('',(-1.,0.,0.));
#517=DIRECTION('',(0.,0.,1.));
#518=AXIS2_PLACEMENT_3D('',#515,#516,#517);
#519=CIRCLE('',#518,10.81024);
#520=CARTESIAN_POINT('',(92.8666106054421,0.,10.81024));
#521=VERTEX_POINT('',#520);
#522=EDGE_CURVE('E166',#521,#521,#519,.T.);
#523=ORIENTED_EDGE('',*,*,#522,.T.);
#524=EDGE_LOOP('',(#523));
#525=FACE_BOUND('',#524,.T.);
#526=ORIENTED_EDGE('',*,*,#505,.F.);
#527=EDGE_LOOP('',(#526));
#528=FACE_BOUND('',#527,.T.);
#529=ADVANCED_FACE('F185',(#525,#528),#514,.T.);
#530=CARTESIAN_POINT('',(92.8666106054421,10.81024,0.));
#531=DIRECTION('',(1.,0.,0.));
#532=DIRECTION('',(0.,0.,-1.));
#533=AXIS2_PLACEMENT_3D('',#530,#531,#532);
#534=PLANE('',#533);
#535=ORIENTED_EDGE('',*,*,#522,.F.);
#536=EDGE_LOOP('',(#535));
#537=FACE_BOUND('',#536,.T.);
#538=ADVANCED_FACE('F145',(#537),#534,.T.);
#539=CARTESIAN_POINT('',(0.,0.,0.));
#540=DIRECTION('',(1.,0.,0.));
#541=DIRECTION('',(0.,1.,0.));
#542=AXIS2_PLACEMENT_3D('',#539,#540,#541);
#543=CONICAL_SURFACE('',#542,19.05,1.13446401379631);
#544=ORIENTED_EDGE('',*,*,#447,.F.);
#545=CARTESIAN_POINT('',(0.,0.,0.));
#546=DIRECTION('',(-1.,0.,0.));
#547=DIRECTION('',(0.,-1.,0.));
#548=AXIS2_PLACEMENT_3D('',#545,#546,#547);
#549=CIRCLE('',#548,19.05);
#550=EDGE_CURVE('E57',#233,#444,#549,.T.);
#551=ORIENTED_EDGE('',*,*,#550,.F.);
#552=ORIENTED_EDGE('',*,*,#234,.F.);
#553=EDGE_LOOP('',(#544,#551,#552));
#554=FACE_BOUND('',#553,.T.);
#555=ADVANCED_FACE('F141',(#554),#543,.T.);
#556=EDGE_CURVE('E109',#444,#114,#549,.T.);
#557=ORIENTED_EDGE('',*,*,#556,.F.);
#558=ORIENTED_EDGE('',*,*,#445,.F.);
#559=ORIENTED_EDGE('',*,*,#119,.F.);
#560=EDGE_LOOP('',(#557,#558,#559));
#561=FACE_BOUND('',#560,.T.);
#562=ADVANCED_FACE('F113',(#561),#543,.T.);
#563=ORIENTED_EDGE('',*,*,#353,.T.);
#564=ORIENTED_EDGE('',*,*,#238,.F.);
#565=EDGE_CURVE('E107',#342,#233,#549,.T.);
#566=ORIENTED_EDGE('',*,*,#565,.F.);
#567=EDGE_LOOP('',(#563,#564,#566));
#568=FACE_BOUND('',#567,.T.);
#569=ADVANCED_FACE('F146',(#568),#543,.T.);
#570=ORIENTED_EDGE('',*,*,#343,.T.);
#571=EDGE_CURVE('E96',#114,#342,#549,.T.);
#572=ORIENTED_EDGE('',*,*,#571,.F.);
#573=ORIENTED_EDGE('',*,*,#115,.F.);
#574=EDGE_LOOP('',(#570,#572,#573));
#575=FACE_BOUND('',#574,.T.);
#576=ADVANCED_FACE('F98',(#575),#543,.T.);
#577=CARTESIAN_POINT('',(0.,-19.05,19.05));
#578=DIRECTION('',(-1.,0.,0.));
#579=DIRECTION('',(0.,0.,1.));
#580=AXIS2_PLACEMENT_3D('',#577,#578,#579);
#581=PLANE('',#580);
#582=ORIENTED_EDGE('',*,*,#571,.T.);
#583=ORIENTED_EDGE('',*,*,#565,.T.);
#584=ORIENTED_EDGE('',*,*,#550,.T.);
#585=ORIENTED_EDGE('',*,*,#556,.T.);
#586=EDGE_LOOP('',(#582,#583,#584,#585));
#587=FACE_BOUND('',#586,.T.);
#588=ADVANCED_FACE('F123',(#587),#581,.T.);
#589=CARTESIAN_POINT('',(15.8440541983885,-12.7,0.));
#590=CARTESIAN_POINT('',(14.5527510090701,-12.7,0.));
#591=CARTESIAN_POINT('',(14.3407360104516,-13.973779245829,0.));
#592=CARTESIAN_POINT('',(15.8440541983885,-12.7,-0.55418458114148));
#593=CARTESIAN_POINT('',(14.5527510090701,-12.7,-0.563562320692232));
#594=CARTESIAN_POINT('',(14.3407360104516,-13.973779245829,-0.620686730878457));
#595=CARTESIAN_POINT('',(15.8508271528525,-12.6636681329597,-1.10836916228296));
#596=CARTESIAN_POINT('',(14.5590086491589,-12.6624043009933,-1.12735199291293));
#597=CARTESIAN_POINT('',(14.3475089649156,-13.9330875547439,-1.24137346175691));
#598=CARTESIAN_POINT('',(15.8777965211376,-12.5189975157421,-2.20725308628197));
#599=CARTESIAN_POINT('',(14.5838983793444,-12.512867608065,-2.24441934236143));
#600=CARTESIAN_POINT('',(14.3744783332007,-13.7710564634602,-2.4721234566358));
#601=CARTESIAN_POINT('',(15.8979992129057,-12.4106250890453,-2.75194787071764));
#602=CARTESIAN_POINT('',(14.6025562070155,-12.4007719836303,-2.7981313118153));
#603=CARTESIAN_POINT('',(14.3946810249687,-13.6496793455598,-3.08218161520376));
#604=CARTESIAN_POINT('',(15.9514760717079,-12.1237614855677,-3.8225388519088));
#605=CARTESIAN_POINT('',(14.6518795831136,-12.1044387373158,-3.8852175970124));
#606=CARTESIAN_POINT('',(14.4481578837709,-13.3283921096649,-4.28124351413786));
#607=CARTESIAN_POINT('',(15.984762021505,-11.9452071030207,-4.3484176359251));
#608=CARTESIAN_POINT('',(14.6825945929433,-11.9199039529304,-4.41896686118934));
#609=CARTESIAN_POINT('',(14.4814438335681,-13.1284112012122,-4.87022775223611));
#610=CARTESIAN_POINT('',(16.0638305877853,-11.5210630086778,-5.37239341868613));
#611=CARTESIAN_POINT('',(14.7554482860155,-11.4822013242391,-5.45671717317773));
#612=CARTESIAN_POINT('',(14.5605123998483,-12.6533698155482,-6.01708062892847));
#613=CARTESIAN_POINT('',(16.1096290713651,-11.275388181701,-5.87045416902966));
#614=CARTESIAN_POINT('',(14.7976563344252,-11.2286167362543,-5.96100031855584));
#615=CARTESIAN_POINT('',(14.6063108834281,-12.3782140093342,-6.57490866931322));
#616=CARTESIAN_POINT('',(16.2129354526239,-10.7212262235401,-6.83029208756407));
#617=CARTESIAN_POINT('',(14.8927073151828,-10.6575535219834,-6.93099597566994));
#618=CARTESIAN_POINT('',(14.7096172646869,-11.757552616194,-7.64992713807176));
#619=CARTESIAN_POINT('',(16.2704614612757,-10.4126419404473,-7.2920115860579));
#620=CARTESIAN_POINT('',(14.9456342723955,-10.3395700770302,-7.39687251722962));
#621=CARTESIAN_POINT('',(14.7671432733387,-11.4119382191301,-8.16705297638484));
#622=CARTESIAN_POINT('',(16.3962369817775,-9.7379497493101,-8.1712886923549));
#623=CARTESIAN_POINT('',(15.061145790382,-9.64558061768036,-8.28198069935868));
#624=CARTESIAN_POINT('',(14.8929187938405,-10.6562829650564,-9.15184333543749));
#625=CARTESIAN_POINT('',(16.4645048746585,-9.37174324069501,-8.58876851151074));
#626=CARTESIAN_POINT('',(15.1238228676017,-9.26901876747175,-8.70124326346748));
#627=CARTESIAN_POINT('',(14.9611866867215,-10.2461316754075,-9.61942073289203));
#628=CARTESIAN_POINT('',(16.6105965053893,-8.58807021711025,-9.37244251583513));
#629=CARTESIAN_POINT('',(15.2576884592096,-8.46475862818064,-9.48594199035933));
#630=CARTESIAN_POINT('',(15.1072783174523,-9.36841788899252,-10.4971356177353));
#631=CARTESIAN_POINT('',(16.6884370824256,-8.1705133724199,-9.73854382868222));
#632=CARTESIAN_POINT('',(15.3289714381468,-8.03649279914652,-9.85127189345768));
#633=CARTESIAN_POINT('',(15.1851188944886,-8.90075422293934,-10.9071690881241));
#634=CARTESIAN_POINT('',(16.8523444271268,-7.29127228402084,-10.413210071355));
#635=CARTESIAN_POINT('',(15.4787564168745,-7.13658949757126,-10.5219435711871));
#636=CARTESIAN_POINT('',(15.3490262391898,-7.91600420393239,-11.6627952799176));
#637=CARTESIAN_POINT('',(16.9384250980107,-6.82951345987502,-10.7216750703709));
#638=CARTESIAN_POINT('',(15.5573484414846,-6.66441115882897,-10.8270485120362));
#639=CARTESIAN_POINT('',(15.4351069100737,-7.39883432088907,-12.0082760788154));
#640=CARTESIAN_POINT('',(17.1173432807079,-5.86975038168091,-11.2757952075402));
#641=CARTESIAN_POINT('',(15.720338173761,-5.68517412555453,-11.372235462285));
#642=CARTESIAN_POINT('',(15.6140250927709,-6.32389967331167,-12.6288906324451));
#643=CARTESIAN_POINT('',(17.2101909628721,-5.37169157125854,-11.5213531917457));
#644=CARTESIAN_POINT('',(15.8048156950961,-5.17763591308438,-11.6119662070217));
#645=CARTESIAN_POINT('',(15.7068727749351,-5.76607380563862,-12.9039155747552));
#646=CARTESIAN_POINT('',(17.401058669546,-4.34782817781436,-11.9454517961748));
#647=CARTESIAN_POINT('',(15.97806979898,-4.13673086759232,-12.0225818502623));
#648=CARTESIAN_POINT('',(15.897740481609,-4.61934680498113,-13.3789060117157));
#649=CARTESIAN_POINT('',(17.4990850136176,-3.82198969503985,-12.1239082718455));
#650=CARTESIAN_POINT('',(16.0669111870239,-3.60297468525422,-12.1930249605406));
#651=CARTESIAN_POINT('',(15.9957668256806,-4.03040770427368,-13.578777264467));
#652=CARTESIAN_POINT('',(17.6986368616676,-2.75154233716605,-12.4107341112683));
#653=CARTESIAN_POINT('',(16.2473226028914,-2.5190687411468,-12.4625147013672));
#654=CARTESIAN_POINT('',(16.1953186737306,-2.83150666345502,-13.9000222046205));
#655=CARTESIAN_POINT('',(17.8001653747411,-2.20691732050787,-12.5190415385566));
#656=CARTESIAN_POINT('',(16.338938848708,-1.96864130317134,-12.5610585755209));
#657=CARTESIAN_POINT('',(16.2968471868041,-2.22152664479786,-14.0213265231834));
#658=CARTESIAN_POINT('',(18.0049877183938,-1.10819767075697,-12.6636908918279));
#659=CARTESIAN_POINT('',(16.5232965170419,-0.861026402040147,-12.6855050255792));
#660=CARTESIAN_POINT('',(16.5016695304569,-0.990960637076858,-14.1833337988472));
#661=CARTESIAN_POINT('',(18.1082823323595,-0.554098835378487,-12.7));
#662=CARTESIAN_POINT('',(16.6160633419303,-0.30368632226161,-12.7108768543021));
#663=CARTESIAN_POINT('',(16.6049641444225,-0.370369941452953,-14.224));
#664=CARTESIAN_POINT('',(18.3148715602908,0.554098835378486,-12.7));
#665=CARTESIAN_POINT('',(16.8011169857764,0.80810997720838,-12.6890449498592));
#666=CARTESIAN_POINT('',(16.8115533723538,0.870811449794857,-14.224));
#667=CARTESIAN_POINT('',(18.4181661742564,1.10819767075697,-12.6636908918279));
#668=CARTESIAN_POINT('',(16.8934075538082,1.36258872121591,-12.6413167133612));
#669=CARTESIAN_POINT('',(16.9148479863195,1.49140214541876,-14.1833337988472));
#670=CARTESIAN_POINT('',(18.6229885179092,2.20691732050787,-12.5190415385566));
#671=CARTESIAN_POINT('',(17.0759328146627,2.45919457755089,-12.4746356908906));
#672=CARTESIAN_POINT('',(17.1196703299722,2.72196815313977,-14.0213265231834));
#673=CARTESIAN_POINT('',(18.7245170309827,2.75154233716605,-12.4107341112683));
#674=CARTESIAN_POINT('',(17.1661501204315,3.00121722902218,-12.3551981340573));
#675=CARTESIAN_POINT('',(17.2211988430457,3.33194817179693,-13.9000222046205));
#676=CARTESIAN_POINT('',(18.9240688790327,3.82198969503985,-12.1239082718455));
#677=CARTESIAN_POINT('',(17.3430120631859,4.06379805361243,-12.0476793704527));
#678=CARTESIAN_POINT('',(17.4207506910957,4.53084921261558,-13.578777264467));
#679=CARTESIAN_POINT('',(19.0220952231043,4.34782817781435,-11.9454517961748));
#680=CARTESIAN_POINT('',(17.4296199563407,4.584135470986,-11.8591840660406));
#681=CARTESIAN_POINT('',(17.5187770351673,5.11978831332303,-13.3789060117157));
#682=CARTESIAN_POINT('',(19.2129629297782,5.37169157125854,-11.5213531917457));
#683=CARTESIAN_POINT('',(17.5978327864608,5.59475270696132,-11.417276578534));
#684=CARTESIAN_POINT('',(17.7096447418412,6.26651531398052,-12.9039155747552));
#685=CARTESIAN_POINT('',(19.3058106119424,5.86975038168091,-11.2757952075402));
#686=CARTESIAN_POINT('',(17.679384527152,6.08471292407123,-11.1635477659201));
#687=CARTESIAN_POINT('',(17.8024924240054,6.82434118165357,-12.6288906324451));
#688=CARTESIAN_POINT('',(19.4847287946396,6.82951345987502,-10.7216750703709));
#689=CARTESIAN_POINT('',(17.8361653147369,7.026646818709,-10.5959366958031));
#690=CARTESIAN_POINT('',(17.9814106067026,7.89927582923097,-12.0082760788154));
#691=CARTESIAN_POINT('',(19.5708094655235,7.29127228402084,-10.413210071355));
#692=CARTESIAN_POINT('',(17.911328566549,7.47822520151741,-10.2818565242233));
#693=CARTESIAN_POINT('',(18.0674912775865,8.4164457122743,-11.6627952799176));
#694=CARTESIAN_POINT('',(19.7347168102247,8.1705133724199,-9.73854382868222));
#695=CARTESIAN_POINT('',(18.0541429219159,8.33624922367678,-9.59921399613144));
#696=CARTESIAN_POINT('',(18.2313986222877,9.40119573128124,-10.9071690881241));
#697=CARTESIAN_POINT('',(19.812557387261,8.58807021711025,-9.37244251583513));
#698=CARTESIAN_POINT('',(18.121720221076,8.74225144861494,-9.23058694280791));
#699=CARTESIAN_POINT('',(18.309239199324,9.86885939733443,-10.4971356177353));
#700=CARTESIAN_POINT('',(19.9586490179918,9.37174324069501,-8.58876851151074));
#701=CARTESIAN_POINT('',(18.248318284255,9.50284851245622,-8.44528882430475));
#702=CARTESIAN_POINT('',(18.4553308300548,10.7465731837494,-9.61942073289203));
#703=CARTESIAN_POINT('',(20.0269169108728,9.7379497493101,-8.17128869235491));
#704=CARTESIAN_POINT('',(18.3072623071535,9.85698229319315,-8.02869308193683));
#705=CARTESIAN_POINT('',(18.5235987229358,11.1567244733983,-9.1518433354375));
#706=CARTESIAN_POINT('',(20.1526924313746,10.4126419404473,-7.2920115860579));
#707=CARTESIAN_POINT('',(18.4157041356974,10.5084972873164,-7.15451860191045));
#708=CARTESIAN_POINT('',(18.6493742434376,11.912379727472,-8.16705297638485));
#709=CARTESIAN_POINT('',(20.2102184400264,10.7212262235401,-6.83029208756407));
#710=CARTESIAN_POINT('',(18.4651275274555,10.8054314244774,-6.69715367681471));
#711=CARTESIAN_POINT('',(18.7069002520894,12.2579941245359,-7.64992713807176));
#712=CARTESIAN_POINT('',(20.3135248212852,11.275388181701,-5.87045416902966));
#713=CARTESIAN_POINT('',(18.5537979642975,11.33816053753,-5.74898662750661));
#714=CARTESIAN_POINT('',(18.8102066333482,12.8786555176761,-6.57490866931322));
#715=CARTESIAN_POINT('',(20.359323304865,11.5210630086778,-5.37239341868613));
#716=CARTESIAN_POINT('',(18.5929780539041,11.5735532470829,-5.25852673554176));
#717=CARTESIAN_POINT('',(18.856005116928,13.1538113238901,-6.01708062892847));
#718=CARTESIAN_POINT('',(20.4383918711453,11.9452071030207,-4.3484176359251));
#719=CARTESIAN_POINT('',(18.6605923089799,11.9797775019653,-4.25207613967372));
#720=CARTESIAN_POINT('',(18.9350736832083,13.6288527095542,-4.87022775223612));
#721=CARTESIAN_POINT('',(20.4716778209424,12.1237614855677,-3.8225388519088));
#722=CARTESIAN_POINT('',(18.688971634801,12.1502795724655,-3.7365377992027));
#723=CARTESIAN_POINT('',(18.9683596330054,13.8288336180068,-4.28124351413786));
#724=CARTESIAN_POINT('',(20.5251546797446,12.4106250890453,-2.75194787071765));
#725=CARTESIAN_POINT('',(18.7345739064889,12.4242565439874,-2.68809190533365));
#726=CARTESIAN_POINT('',(19.0218364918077,14.1501208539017,-3.08218161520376));
#727=CARTESIAN_POINT('',(20.5453573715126,12.5189975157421,-2.20725308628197));
#728=CARTESIAN_POINT('',(18.751757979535,12.5274978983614,-2.15572126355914));
#729=CARTESIAN_POINT('',(19.0420391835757,14.2714979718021,-2.47212345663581));
#730=CARTESIAN_POINT('',(20.5723267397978,12.6636681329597,-1.10836916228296));
#731=CARTESIAN_POINT('',(18.7747162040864,12.6654301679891,-1.08194171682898));
#732=CARTESIAN_POINT('',(19.0690085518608,14.4335290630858,-1.24137346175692));
#733=CARTESIAN_POINT('',(20.5790996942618,12.7,-0.554184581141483));
#734=CARTESIAN_POINT('',(18.780470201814,12.7,-0.541122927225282));
#735=CARTESIAN_POINT('',(19.0757815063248,14.474220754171,-0.620686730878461));
#736=CARTESIAN_POINT('',(20.5790996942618,12.7,0.55418458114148));
#737=CARTESIAN_POINT('',(18.780470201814,12.7,0.541122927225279));
#738=CARTESIAN_POINT('',(19.0757815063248,14.474220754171,0.620686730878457));
#739=CARTESIAN_POINT('',(20.5723267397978,12.6636681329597,1.10836916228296));
#740=CARTESIAN_POINT('',(18.7747162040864,12.6654301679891,1.08194171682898));
#741=CARTESIAN_POINT('',(19.0690085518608,14.4335290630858,1.24137346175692));
#742=CARTESIAN_POINT('',(20.5453573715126,12.5189975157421,2.20725308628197));
#743=CARTESIAN_POINT('',(18.751757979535,12.5274978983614,2.15572126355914));
#744=CARTESIAN_POINT('',(19.0420391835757,14.2714979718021,2.4721234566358));
#745=CARTESIAN_POINT('',(20.5251546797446,12.4106250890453,2.75194787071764));
#746=CARTESIAN_POINT('',(18.7345739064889,12.4242565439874,2.68809190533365));
#747=CARTESIAN_POINT('',(19.0218364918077,14.1501208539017,3.08218161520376));
#748=CARTESIAN_POINT('',(20.4716778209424,12.1237614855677,3.8225388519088));
#749=CARTESIAN_POINT('',(18.688971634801,12.1502795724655,3.7365377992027));
#750=CARTESIAN_POINT('',(18.9683596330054,13.8288336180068,4.28124351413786));
#751=CARTESIAN_POINT('',(20.4383918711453,11.9452071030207,4.3484176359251));
#752=CARTESIAN_POINT('',(18.6605923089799,11.9797775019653,4.25207613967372));
#753=CARTESIAN_POINT('',(18.9350736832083,13.6288527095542,4.87022775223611));
#754=CARTESIAN_POINT('',(20.359323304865,11.5210630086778,5.37239341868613));
#755=CARTESIAN_POINT('',(18.5929780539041,11.5735532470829,5.25852673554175));
#756=CARTESIAN_POINT('',(18.856005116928,13.1538113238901,6.01708062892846));
#757=CARTESIAN_POINT('',(20.3135248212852,11.275388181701,5.87045416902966));
#758=CARTESIAN_POINT('',(18.5537979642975,11.33816053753,5.7489866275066));
#759=CARTESIAN_POINT('',(18.8102066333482,12.8786555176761,6.57490866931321));
#760=CARTESIAN_POINT('',(20.2102184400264,10.7212262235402,6.83029208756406));
#761=CARTESIAN_POINT('',(18.4651275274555,10.8054314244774,6.69715367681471));
#762=CARTESIAN_POINT('',(18.7069002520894,12.2579941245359,7.64992713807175));
#763=CARTESIAN_POINT('',(20.1526924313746,10.4126419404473,7.29201158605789));
#764=CARTESIAN_POINT('',(18.4157041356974,10.5084972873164,7.15451860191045));
#765=CARTESIAN_POINT('',(18.6493742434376,11.912379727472,8.16705297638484));
#766=CARTESIAN_POINT('',(20.0269169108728,9.7379497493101,8.1712886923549));
#767=CARTESIAN_POINT('',(18.3072623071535,9.85698229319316,8.02869308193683));
#768=CARTESIAN_POINT('',(18.5235987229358,11.1567244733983,9.15184333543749));
#769=CARTESIAN_POINT('',(19.9586490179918,9.37174324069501,8.58876851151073));
#770=CARTESIAN_POINT('',(18.248318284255,9.50284851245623,8.44528882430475));
#771=CARTESIAN_POINT('',(18.4553308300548,10.7465731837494,9.61942073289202));
#772=CARTESIAN_POINT('',(19.812557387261,8.58807021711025,9.37244251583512));
#773=CARTESIAN_POINT('',(18.121720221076,8.74225144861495,9.23058694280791));
#774=CARTESIAN_POINT('',(18.309239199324,9.86885939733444,10.4971356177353));
#775=CARTESIAN_POINT('',(19.7347168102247,8.1705133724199,9.73854382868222));
#776=CARTESIAN_POINT('',(18.0541429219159,8.33624922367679,9.59921399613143));
#777=CARTESIAN_POINT('',(18.2313986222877,9.40119573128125,10.9071690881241));
#778=CARTESIAN_POINT('',(19.5708094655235,7.29127228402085,10.413210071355));
#779=CARTESIAN_POINT('',(17.911328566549,7.47822520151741,10.2818565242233));
#780=CARTESIAN_POINT('',(18.0674912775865,8.4164457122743,11.6627952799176));
#781=CARTESIAN_POINT('',(19.4847287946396,6.82951345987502,10.7216750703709));
#782=CARTESIAN_POINT('',(17.8361653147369,7.026646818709,10.5959366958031));
#783=CARTESIAN_POINT('',(17.9814106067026,7.89927582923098,12.0082760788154));
#784=CARTESIAN_POINT('',(19.3058106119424,5.86975038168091,11.2757952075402));
#785=CARTESIAN_POINT('',(17.679384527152,6.08471292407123,11.1635477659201));
#786=CARTESIAN_POINT('',(17.8024924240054,6.82434118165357,12.6288906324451));
#787=CARTESIAN_POINT('',(19.2129629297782,5.37169157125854,11.5213531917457));
#788=CARTESIAN_POINT('',(17.5978327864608,5.59475270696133,11.417276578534));
#789=CARTESIAN_POINT('',(17.7096447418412,6.26651531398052,12.9039155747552));
#790=CARTESIAN_POINT('',(19.0220952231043,4.34782817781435,11.9454517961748));
#791=CARTESIAN_POINT('',(17.4296199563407,4.584135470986,11.8591840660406));
#792=CARTESIAN_POINT('',(17.5187770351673,5.11978831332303,13.3789060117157));
#793=CARTESIAN_POINT('',(18.9240688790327,3.82198969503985,12.1239082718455));
#794=CARTESIAN_POINT('',(17.3430120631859,4.06379805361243,12.0476793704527));
#795=CARTESIAN_POINT('',(17.4207506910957,4.53084921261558,13.578777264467));
#796=CARTESIAN_POINT('',(18.7245170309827,2.75154233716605,12.4107341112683));
#797=CARTESIAN_POINT('',(17.1661501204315,3.00121722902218,12.3551981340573));
#798=CARTESIAN_POINT('',(17.2211988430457,3.33194817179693,13.9000222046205));
#799=CARTESIAN_POINT('',(18.6229885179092,2.20691732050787,12.5190415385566));
#800=CARTESIAN_POINT('',(17.0759328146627,2.45919457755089,12.4746356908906));
#801=CARTESIAN_POINT('',(17.1196703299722,2.72196815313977,14.0213265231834));
#802=CARTESIAN_POINT('',(18.4181661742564,1.10819767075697,12.6636908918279));
#803=CARTESIAN_POINT('',(16.8934075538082,1.36258872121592,12.6413167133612));
#804=CARTESIAN_POINT('',(16.9148479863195,1.49140214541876,14.1833337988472));
#805=CARTESIAN_POINT('',(18.3148715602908,0.554098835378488,12.7));
#806=CARTESIAN_POINT('',(16.8011169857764,0.808109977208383,12.6890449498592));
#807=CARTESIAN_POINT('',(16.8115533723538,0.87081144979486,14.224));
#808=CARTESIAN_POINT('',(18.1082823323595,-0.554098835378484,12.7));
#809=CARTESIAN_POINT('',(16.6160633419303,-0.303686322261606,12.7108768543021));
#810=CARTESIAN_POINT('',(16.6049641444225,-0.370369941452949,14.224));
#811=CARTESIAN_POINT('',(18.0049877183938,-1.10819767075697,12.6636908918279));
#812=CARTESIAN_POINT('',(16.5232965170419,-0.861026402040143,12.6855050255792));
#813=CARTESIAN_POINT('',(16.5016695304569,-0.990960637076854,14.1833337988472));
#814=CARTESIAN_POINT('',(17.8001653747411,-2.20691732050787,12.5190415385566));
#815=CARTESIAN_POINT('',(16.338938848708,-1.96864130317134,12.5610585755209));
#816=CARTESIAN_POINT('',(16.2968471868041,-2.22152664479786,14.0213265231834));
#817=CARTESIAN_POINT('',(17.6986368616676,-2.75154233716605,12.4107341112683));
#818=CARTESIAN_POINT('',(16.2473226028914,-2.51906874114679,12.4625147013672));
#819=CARTESIAN_POINT('',(16.1953186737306,-2.83150666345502,13.9000222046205));
#820=CARTESIAN_POINT('',(17.4990850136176,-3.82198969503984,12.1239082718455));
#821=CARTESIAN_POINT('',(16.066911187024,-3.60297468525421,12.1930249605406));
#822=CARTESIAN_POINT('',(15.9957668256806,-4.03040770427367,13.578777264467));
#823=CARTESIAN_POINT('',(17.401058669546,-4.34782817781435,11.9454517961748));
#824=CARTESIAN_POINT('',(15.97806979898,-4.13673086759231,12.0225818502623));
#825=CARTESIAN_POINT('',(15.897740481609,-4.61934680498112,13.3789060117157));
#826=CARTESIAN_POINT('',(17.2101909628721,-5.37169157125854,11.5213531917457));
#827=CARTESIAN_POINT('',(15.8048156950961,-5.17763591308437,11.6119662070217));
#828=CARTESIAN_POINT('',(15.7068727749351,-5.76607380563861,12.9039155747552));
#829=CARTESIAN_POINT('',(17.1173432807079,-5.86975038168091,11.2757952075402));
#830=CARTESIAN_POINT('',(15.720338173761,-5.68517412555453,11.372235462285));
#831=CARTESIAN_POINT('',(15.6140250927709,-6.32389967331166,12.6288906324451));
#832=CARTESIAN_POINT('',(16.9384250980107,-6.82951345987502,10.7216750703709));
#833=CARTESIAN_POINT('',(15.5573484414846,-6.66441115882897,10.8270485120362));
#834=CARTESIAN_POINT('',(15.4351069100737,-7.39883432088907,12.0082760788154));
#835=CARTESIAN_POINT('',(16.8523444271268,-7.29127228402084,10.413210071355));
#836=CARTESIAN_POINT('',(15.4787564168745,-7.13658949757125,10.5219435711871));
#837=CARTESIAN_POINT('',(15.3490262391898,-7.91600420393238,11.6627952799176));
#838=CARTESIAN_POINT('',(16.6884370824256,-8.17051337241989,9.73854382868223));
#839=CARTESIAN_POINT('',(15.3289714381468,-8.03649279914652,9.85127189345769));
#840=CARTESIAN_POINT('',(15.1851188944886,-8.90075422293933,10.9071690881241));
#841=CARTESIAN_POINT('',(16.6105965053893,-8.58807021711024,9.37244251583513));
#842=CARTESIAN_POINT('',(15.2576884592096,-8.46475862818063,9.48594199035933));
#843=CARTESIAN_POINT('',(15.1072783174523,-9.36841788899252,10.4971356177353));
#844=CARTESIAN_POINT('',(16.4645048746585,-9.371743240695,8.58876851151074));
#845=CARTESIAN_POINT('',(15.1238228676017,-9.26901876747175,8.70124326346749));
#846=CARTESIAN_POINT('',(14.9611866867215,-10.2461316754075,9.61942073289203));
#847=CARTESIAN_POINT('',(16.3962369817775,-9.73794974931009,8.17128869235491));
#848=CARTESIAN_POINT('',(15.061145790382,-9.64558061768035,8.28198069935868));
#849=CARTESIAN_POINT('',(14.8929187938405,-10.6562829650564,9.1518433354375));
#850=CARTESIAN_POINT('',(16.2704614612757,-10.4126419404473,7.2920115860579));
#851=CARTESIAN_POINT('',(14.9456342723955,-10.3395700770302,7.39687251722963));
#852=CARTESIAN_POINT('',(14.7671432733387,-11.4119382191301,8.16705297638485));
#853=CARTESIAN_POINT('',(16.2129354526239,-10.7212262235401,6.83029208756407));
#854=CARTESIAN_POINT('',(14.8927073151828,-10.6575535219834,6.93099597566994));
#855=CARTESIAN_POINT('',(14.7096172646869,-11.757552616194,7.64992713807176));
#856=CARTESIAN_POINT('',(16.1096290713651,-11.275388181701,5.87045416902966));
#857=CARTESIAN_POINT('',(14.7976563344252,-11.2286167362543,5.96100031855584));
#858=CARTESIAN_POINT('',(14.6063108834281,-12.3782140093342,6.57490866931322));
#859=CARTESIAN_POINT('',(16.0638305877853,-11.5210630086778,5.37239341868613));
#860=CARTESIAN_POINT('',(14.7554482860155,-11.4822013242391,5.45671717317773));
#861=CARTESIAN_POINT('',(14.5605123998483,-12.6533698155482,6.01708062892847));
#862=CARTESIAN_POINT('',(15.984762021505,-11.9452071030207,4.3484176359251));
#863=CARTESIAN_POINT('',(14.6825945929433,-11.9199039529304,4.41896686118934));
#864=CARTESIAN_POINT('',(14.4814438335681,-13.1284112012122,4.87022775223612));
#865=CARTESIAN_POINT('',(15.9514760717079,-12.1237614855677,3.82253885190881));
#866=CARTESIAN_POINT('',(14.6518795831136,-12.1044387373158,3.88521759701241));
#867=CARTESIAN_POINT('',(14.4481578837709,-13.3283921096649,4.28124351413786));
#868=CARTESIAN_POINT('',(15.8979992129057,-12.4106250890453,2.75194787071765));
#869=CARTESIAN_POINT('',(14.6025562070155,-12.4007719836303,2.7981313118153));
#870=CARTESIAN_POINT('',(14.3946810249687,-13.6496793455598,3.08218161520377));
#871=CARTESIAN_POINT('',(15.8777965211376,-12.5189975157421,2.20725308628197));
#872=CARTESIAN_POINT('',(14.5838983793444,-12.512867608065,2.24441934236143));
#873=CARTESIAN_POINT('',(14.3744783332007,-13.7710564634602,2.47212345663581));
#874=CARTESIAN_POINT('',(15.8508271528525,-12.6636681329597,1.10836916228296));
#875=CARTESIAN_POINT('',(14.5590086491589,-12.6624043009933,1.12735199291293));
#876=CARTESIAN_POINT('',(14.3475089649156,-13.9330875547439,1.24137346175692));
#877=CARTESIAN_POINT('',(15.8440541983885,-12.7,0.554184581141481));
#878=CARTESIAN_POINT('',(14.5527510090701,-12.7,0.563562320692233));
#879=CARTESIAN_POINT('',(14.3407360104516,-13.973779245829,0.620686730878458));
#880=CARTESIAN_POINT('',(15.8440541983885,-12.7,0.));
#881=CARTESIAN_POINT('',(14.5527510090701,-12.7,0.));
#882=CARTESIAN_POINT('',(14.3407360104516,-13.973779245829,0.));
#883=(BOUNDED_SURFACE() B_SPLINE_SURFACE(3,2,((#589,#590,#591),(#592,#593,#594),(#595,#596,
#597),(#598,#599,#600),(#601,#602,#603),(#604,#605,#606),(#607,#608,#609),(#610,#611,#612),
(#613,#614,#615),(#616,#617,#618),(#619,#620,#621),(#622,#623,#624),(#625,#626,#627),(#628,#629,
#630),(#631,#632,#633),(#634,#635,#636),(#637,#638,#639),(#640,#641,#642),(#643,#644,#645),
(#646,#647,#648),(#649,#650,#651),(#652,#653,#654),(#655,#656,#657),(#658,#659,#660),(#661,#662,
#663),(#664,#665,#666),(#667,#668,#669),(#670,#671,#672),(#673,#674,#675),(#676,#677,#678),
(#679,#680,#681),(#682,#683,#684),(#685,#686,#687),(#688,#689,#690),(#691,#692,#693),(#694,#695,
#696),(#697,#698,#699),(#700,#701,#702),(#703,#704,#705),(#706,#707,#708),(#709,#710,#711),
(#712,#713,#714),(#715,#716,#717),(#718,#719,#720),(#721,#722,#723),(#724,#725,#726),(#727,#728,
#729),(#730,#731,#732),(#733,#734,#735),(#736,#737,#738),(#739,#740,#741),(#742,#743,#744),
(#745,#746,#747),(#748,#749,#750),(#751,#752,#753),(#754,#755,#756),(#757,#758,#759),(#760,#761,
#762),(#763,#764,#765),(#766,#767,#768),(#769,#770,#771),(#772,#773,#774),(#775,#776,#777),
(#778,#779,#780),(#781,#782,#783),(#784,#785,#786),(#787,#788,#789),(#790,#791,#792),(#793,#794,
#795),(#796,#797,#798),(#799,#800,#801),(#802,#803,#804),(#805,#806,#807),(#808,#809,#810),
(#811,#812,#813),(#814,#815,#816),(#817,#818,#819),(#820,#821,#822),(#823,#824,#825),(#826,#827,
#828),(#829,#830,#831),(#832,#833,#834),(#835,#836,#837),(#838,#839,#840),(#841,#842,#843),
(#844,#845,#846),(#847,#848,#849),(#850,#851,#852),(#853,#854,#855),(#856,#857,#858),(#859,#860,
#861),(#862,#863,#864),(#865,#866,#867),(#868,#869,#870),(#871,#872,#873),(#874,#875,#876),
(#877,#878,#879),(#880,#881,#882)),.UNSPECIFIED.,.T.,.F.,.F.) B_SPLINE_SURFACE_WITH_KNOTS((4,2,
2,2,2,2,2,2,2,2,2,2,2,2,2,2,2,2,2,2,2,2,2,2,2,2,2,2,2,2,2,2,2,2,2,2,2,2,2,2,2,2,2,2,2,2,2,2,4),
(3,3),(0.,1.86069846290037,3.72226735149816,5.58551662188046,7.45113972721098,9.31966606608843,
11.1914252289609,13.0665253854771,14.9448470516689,16.8260523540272,18.7096088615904,
20.5948261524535,22.48090255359,24.3669789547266,26.2521962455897,28.1357527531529,
30.0169580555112,31.895279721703,33.7703798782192,35.6421390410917,37.5106653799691,
39.3762884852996,41.2395377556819,43.1011066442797,44.9618051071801,46.8225035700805,
48.6840724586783,50.5473217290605,52.4129448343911,54.2814711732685,56.153230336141,
58.0283304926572,59.9066521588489,61.7878574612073,63.6714139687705,65.5566312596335,
67.4427076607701,69.3287840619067,71.2140013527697,73.097557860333,74.9787631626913,
76.8570848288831,78.7321849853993,80.6039441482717,82.4724704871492,84.3380935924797,
86.201342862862,88.0629117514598,89.9236102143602),(0.,1.),
.UNSPECIFIED.) GEOMETRIC_REPRESENTATION_ITEM() RATIONAL_B_SPLINE_SURFACE(((1.,0.76295047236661,
1.),(1.,0.76295047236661,1.),(1.,0.762796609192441,1.),(1.,0.762183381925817,1.),(1.,
0.761723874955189,1.),(1.,0.760505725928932,1.),(1.,0.759746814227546,1.),(1.,0.757940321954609,
1.),(1.,0.756892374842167,1.),(1.,0.754522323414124,1.),(1.,0.753199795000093,1.),(1.,
0.750299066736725,1.),(1.,0.748720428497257,1.),(1.,0.745329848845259,1.),(1.,0.743517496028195,
1.),(1.,0.739685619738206,1.),(1.,0.737665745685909,1.),(1.,0.73344856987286,1.),(1.,
0.731251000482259,1.),(1.,0.726711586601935,1.),(1.,0.724369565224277,1.),(1.,0.719577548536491,
1.),(1.,0.71712745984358,1.),(1.,0.712158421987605,1.),(1.,0.709639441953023,1.),(1.,
0.704574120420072,1.),(1.,0.702027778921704,1.),(1.,0.696951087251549,1.),(1.,0.69442073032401,
1.),(1.,0.689420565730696,1.),(1.,0.686950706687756,1.),(1.,0.682116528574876,1.),(1.,
0.679752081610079,1.),(1.,0.675173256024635,1.),(1.,0.672958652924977,1.),(1.,0.668722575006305,
1.),(1.,0.666700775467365,1.),(1.,0.662890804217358,1.),(1.,0.661102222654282,1.),(1.,
0.657795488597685,1.),(1.,0.65627687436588,1.),(1.,0.653542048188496,1.),(1.,0.6523253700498,
1.),(1.,0.650220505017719,1.),(1.,0.649331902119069,1.),(1.,0.647902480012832,1.),(1.,
0.647361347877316,1.),(1.,0.64663866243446,1.),(1.,0.646456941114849,1.),(1.,0.646456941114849,
1.),(1.,0.64663866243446,1.),(1.,0.647361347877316,1.),(1.,0.647902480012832,1.),(1.,
0.649331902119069,1.),(1.,0.650220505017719,1.),(1.,0.6523253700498,1.),(1.,0.653542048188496,
1.),(1.,0.65627687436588,1.),(1.,0.657795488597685,1.),(1.,0.661102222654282,1.),(1.,
0.662890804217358,1.),(1.,0.666700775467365,1.),(1.,0.668722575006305,1.),(1.,0.672958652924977,
1.),(1.,0.675173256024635,1.),(1.,0.679752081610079,1.),(1.,0.682116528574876,1.),(1.,
0.686950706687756,1.),(1.,0.689420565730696,1.),(1.,0.69442073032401,1.),(1.,0.696951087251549,
1.),(1.,0.702027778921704,1.),(1.,0.704574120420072,1.),(1.,0.709639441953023,1.),(1.,
0.712158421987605,1.),(1.,0.71712745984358,1.),(1.,0.719577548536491,1.),(1.,0.724369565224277,
1.),(1.,0.726711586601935,1.),(1.,0.731251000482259,1.),(1.,0.73344856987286,1.),(1.,
0.737665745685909,1.),(1.,0.739685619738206,1.),(1.,0.743517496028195,1.),(1.,0.745329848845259,
1.),(1.,0.748720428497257,1.),(1.,0.750299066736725,1.),(1.,0.753199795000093,1.),(1.,
0.754522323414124,1.),(1.,0.756892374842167,1.),(1.,0.757940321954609,1.),(1.,0.759746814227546,
1.),(1.,0.760505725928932,1.),(1.,0.761723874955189,1.),(1.,0.762183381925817,1.),(1.,
0.762796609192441,1.),(1.,0.76295047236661,1.),(1.,0.76295047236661,1.))) REPRESENTATION_ITEM('') SURFACE());
#884=CARTESIAN_POINT('',(15.8440541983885,-14.224,0.));
#885=DIRECTION('',(0.,0.,-1.));
#886=DIRECTION('',(-0.986429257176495,0.164186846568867,0.));
#887=AXIS2_PLACEMENT_3D('',#884,#885,#886);
#888=CIRCLE('',#887,1.524);
#889=EDGE_CURVE('',#470,#493,#888,.T.);
#890=ORIENTED_EDGE('',*,*,#471,.F.);
#891=ORIENTED_EDGE('',*,*,#494,.F.);
#892=ORIENTED_EDGE('',*,*,#889,.T.);
#893=ORIENTED_EDGE('',*,*,#889,.F.);
#894=EDGE_LOOP('',(#890,#892,#891,#893));
#895=FACE_BOUND('',#894,.T.);
#896=ADVANCED_FACE('F41',(#895),#883,.F.);
#897=CLOSED_SHELL('',(#137,#256,#357,#458,#481,#509,#529,#538,#555,#562,#569,#576,#588,#896));
#898=MANIFOLD_SOLID_BREP('B2',#897);
#899=ADVANCED_BREP_SHAPE_REPRESENTATION('',(#18,#898),#14);
#900=SHAPE_DEFINITION_REPRESENTATION(#9,#899);
ENDSEC;
END-ISO-10303-21;
